VERSION 5.7 ;
  NOWIREEXTENSIONATPIN ON ;
  DIVIDERCHAR "/" ;
  BUSBITCHARS "[]" ;
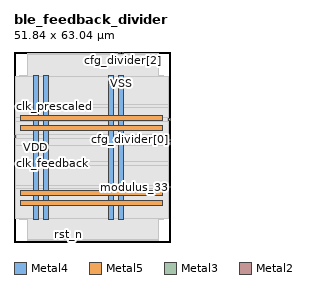
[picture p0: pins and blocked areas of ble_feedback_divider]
MACRO ble_feedback_divider
  CLASS BLOCK ;
  FOREIGN ble_feedback_divider ;
  ORIGIN 0.000 0.000 ;
  SIZE 51.840 BY 63.040 ;
  PIN VDD
    DIRECTION INOUT ;
    USE POWER ;
    PORT
      LAYER Metal4 ;
        RECT 6.440 7.540 8.040 55.180 ;
    END
    PORT
      LAYER Metal4 ;
        RECT 31.440 7.540 33.040 55.180 ;
    END
    PORT
      LAYER Metal5 ;
        RECT 2.240 12.040 49.280 13.640 ;
    END
    PORT
      LAYER Metal5 ;
        RECT 2.240 37.040 49.280 38.640 ;
    END
  END VDD
  PIN VSS
    DIRECTION INOUT ;
    USE GROUND ;
    PORT
      LAYER Metal4 ;
        RECT 9.740 7.540 11.340 55.180 ;
    END
    PORT
      LAYER Metal4 ;
        RECT 34.740 7.540 36.340 55.180 ;
    END
    PORT
      LAYER Metal5 ;
        RECT 2.240 15.340 49.280 16.940 ;
    END
    PORT
      LAYER Metal5 ;
        RECT 2.240 40.340 49.280 41.940 ;
    END
  END VSS
  PIN cfg_divider[0]
    DIRECTION INPUT ;
    USE SIGNAL ;
    ANTENNAGATEAREA 0.898000 ;
    PORT
      LAYER Metal3 ;
        RECT 51.280 33.600 51.840 34.160 ;
    END
  END cfg_divider[0]
  PIN cfg_divider[1]
    DIRECTION INPUT ;
    USE SIGNAL ;
    ANTENNAGATEAREA 1.598000 ;
    PORT
      LAYER Metal2 ;
        RECT 34.720 62.480 35.280 63.040 ;
    END
  END cfg_divider[1]
  PIN cfg_divider[2]
    DIRECTION INPUT ;
    USE SIGNAL ;
    ANTENNAGATEAREA 1.598000 ;
    PORT
      LAYER Metal2 ;
        RECT 35.840 62.480 36.400 63.040 ;
    END
  END cfg_divider[2]
  PIN cfg_divider[3]
    DIRECTION INPUT ;
    USE SIGNAL ;
    ANTENNAGATEAREA 1.598000 ;
    PORT
      LAYER Metal3 ;
        RECT 51.280 40.320 51.840 40.880 ;
    END
  END cfg_divider[3]
  PIN cfg_divider[4]
    DIRECTION INPUT ;
    USE SIGNAL ;
    ANTENNAGATEAREA 1.931500 ;
    PORT
      LAYER Metal3 ;
        RECT 51.280 32.480 51.840 33.040 ;
    END
  END cfg_divider[4]
  PIN cfg_divider[5]
    DIRECTION INPUT ;
    USE SIGNAL ;
    ANTENNAGATEAREA 2.496000 ;
    PORT
      LAYER Metal3 ;
        RECT 0.000 34.720 0.560 35.280 ;
    END
  END cfg_divider[5]
  PIN clk_feedback
    DIRECTION OUTPUT ;
    USE SIGNAL ;
    ANTENNAGATEAREA 0.913500 ;
    ANTENNADIFFAREA 0.893200 ;
    PORT
      LAYER Metal3 ;
        RECT 0.000 25.760 0.560 26.320 ;
    END
  END clk_feedback
  PIN clk_prescaled
    DIRECTION INPUT ;
    USE SIGNAL ;
    ANTENNAGATEAREA 1.183000 ;
    PORT
      LAYER Metal3 ;
        RECT 0.000 44.800 0.560 45.360 ;
    END
  END clk_prescaled
  PIN modulus_33
    DIRECTION OUTPUT ;
    USE SIGNAL ;
    ANTENNAGATEAREA 0.898000 ;
    ANTENNADIFFAREA 0.893200 ;
    PORT
      LAYER Metal3 ;
        RECT 51.280 17.920 51.840 18.480 ;
    END
  END modulus_33
  PIN rst_n
    DIRECTION INPUT ;
    USE SIGNAL ;
    ANTENNAGATEAREA 2.644000 ;
    PORT
      LAYER Metal2 ;
        RECT 17.920 0.000 18.480 0.560 ;
    END
  END rst_n
  OBS
      LAYER Nwell ;
        RECT 1.810 7.410 49.710 55.310 ;
      LAYER Metal1 ;
        RECT 2.240 7.540 49.280 55.180 ;
      LAYER Metal2 ;
        RECT 4.620 62.180 34.420 62.480 ;
        RECT 36.700 62.180 48.020 62.480 ;
        RECT 4.620 0.860 48.020 62.180 ;
        RECT 4.620 0.560 17.620 0.860 ;
        RECT 18.780 0.560 48.020 0.860 ;
      LAYER Metal3 ;
        RECT 0.560 45.660 51.280 55.020 ;
        RECT 0.860 44.500 51.280 45.660 ;
        RECT 0.560 41.180 51.280 44.500 ;
        RECT 0.560 40.020 50.980 41.180 ;
        RECT 0.560 35.580 51.280 40.020 ;
        RECT 0.860 34.460 51.280 35.580 ;
        RECT 0.860 34.420 50.980 34.460 ;
        RECT 0.560 32.180 50.980 34.420 ;
        RECT 0.560 26.620 51.280 32.180 ;
        RECT 0.860 25.460 51.280 26.620 ;
        RECT 0.560 18.780 51.280 25.460 ;
        RECT 0.560 17.620 50.980 18.780 ;
        RECT 0.560 7.700 51.280 17.620 ;
  END
END ble_feedback_divider
END LIBRARY

